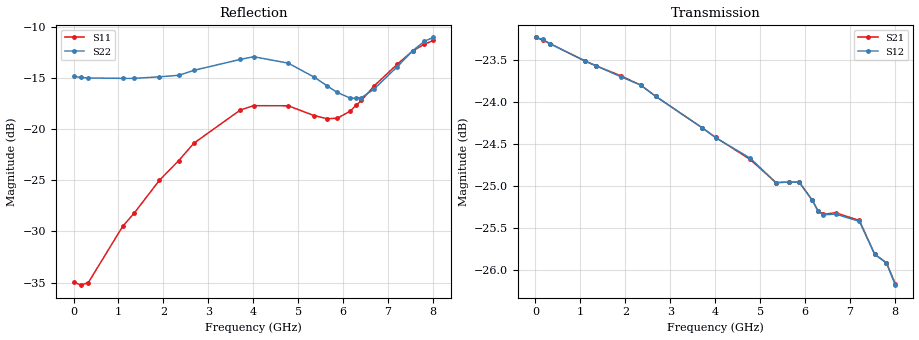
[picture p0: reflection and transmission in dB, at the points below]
! DEVICE ID: PE43712
! File Path: z:\PE43713\PE43713_CHAR_NOM_04292014\AMB\3p300\LS_ATT_22p00dB\PE43713_AMB_3p300V_3p000V_0p000V_LS_ATT_22p00dB_S2P_SN_10_A0139A.s2p
! Serial: 10
! Lot: A0139A
! Temp: 25C
! VDD: 3.300
! VSS: 0.000
! Control_Hi: 3.000
! Control_Lo: 0.000
! Attenuation Step: 22.00dB
! Port 1: RF1
! Port 2: RF2
! ThroughPath:1-2
! IDD: 0.0001468932
! ISS: -1.669e-007
#  Hz  S  RI  R  50
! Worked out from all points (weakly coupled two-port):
!   801 points, 10 MHz to 8.01 GHz, reference 50 ohm
!   highest |S21| = -23.24 dB at 10 MHz (marker M1); lowest = -26.2 dB at 8.01 GHz (marker M2)
!   lowest |S11| = -35.3 dB at 160 MHz (marker M3), VSWR 1.04, Z = 48.4 + j0.523 ohm
!   |S11| at or under -10 dB: start of sweep to end of sweep
!   |S22| runs from -17.0 to -11.0 dB; largest |S21 - S12| = 0.00026
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1e7  -0.0179 0.000685  0.0689 -0.000348  0.0689 -0.000317  -0.1809 0.00129
1.6e8  -0.0164 0.00541  0.0685 -0.00411  0.0686 -0.0041  -0.1786 0.0124
3.3e8  -0.0149 0.00969  0.0678 -0.00828  0.0678 -0.0082  -0.1763 0.0229
1.1e9  -0.00993 0.0321  0.0619 -0.0249  0.0619 -0.0249  -0.1614 0.0728
1.35e9  -0.00632 0.0383  0.0593 -0.0296  0.0593 -0.0296  -0.1543 0.0868
1.91e9  0.00516 0.0559  0.0523 -0.0392  0.0522 -0.0392  -0.1323 0.1223
2.34e9  0.0167 0.0681  0.0457 -0.0456  0.0457 -0.0456  -0.1117 0.1452
2.68e9  0.0272 0.0809  0.04 -0.0494  0.04 -0.0494  -0.0939 0.1696
3.71e9  0.0448 0.1155  0.0209 -0.0572  0.0209 -0.0572  -0.0583 0.2112
4.01e9  0.0473 0.1213  0.0154 -0.0581  0.0153 -0.0581  -0.0541 0.2193
4.78e9  0.0542 0.1182  0.00159 -0.0583  0.00158 -0.0584  -0.0325 0.2076
5.35e9  0.0685 0.0943  -0.00758 -0.056  -0.00757 -0.056  -0.0114 0.1795
5.64e9  0.08 0.0791  -0.0118 -0.0553  -0.0118 -0.0553  0.00977 0.1626
5.87e9  0.0908 0.0671  -0.0161 -0.0542  -0.0161 -0.0542  0.0303 0.148
6.16e9  0.1087 0.0565  -0.0215 -0.0508  -0.0213 -0.0509  0.0611 0.128
6.29e9  0.1198 0.0527  -0.0225 -0.0495  -0.0224 -0.0495  0.0771 0.1184
6.41e9  0.1285 0.0506  -0.0236 -0.0487  -0.0235 -0.0487  0.0912 0.1097
6.68e9  0.1549 0.0465  -0.0274 -0.0468  -0.0272 -0.0468  0.1243 0.0947
7.21e9  0.2028 0.0461  -0.0352 -0.0405  -0.0351 -0.0405  0.1832 0.0856
7.55e9  0.2355 0.0517  -0.0377 -0.0347  -0.0377 -0.0347  0.2245 0.0897
7.81e9  0.2536 0.058  -0.0395 -0.0317  -0.0395 -0.0317  0.2514 0.0952
8.01e9  0.2637 0.0632  -0.0399 -0.0288  -0.0398 -0.0288  0.2641 0.0955
